VERSION 5.7 ;
BUSBITCHARS "[]" ;
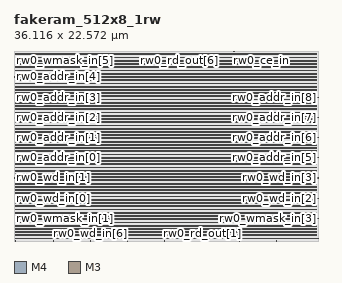
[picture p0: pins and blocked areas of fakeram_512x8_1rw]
MACRO fakeram_512x8_1rw
  FOREIGN fakeram_512x8_1rw 0 0 ;
  SYMMETRY X Y R90 ;
  SIZE 36.116 BY 22.572 ;
  CLASS BLOCK ;
  PIN rw0_wmask_in[0]
    DIRECTION INPUT ;
    USE SIGNAL ;
    SHAPE ABUTMENT ;
    PORT
      LAYER M4 ;
      RECT 0.000 0.276 0.072 0.300 ;
    END
  END rw0_wmask_in[0]
  PIN rw0_wmask_in[1]
    DIRECTION INPUT ;
    USE SIGNAL ;
    SHAPE ABUTMENT ;
    PORT
      LAYER M4 ;
      RECT 0.000 2.676 0.072 2.700 ;
    END
  END rw0_wmask_in[1]
  PIN rw0_wmask_in[2]
    DIRECTION INPUT ;
    USE SIGNAL ;
    SHAPE ABUTMENT ;
    PORT
      LAYER M4 ;
      RECT 36.044 0.276 36.116 0.300 ;
    END
  END rw0_wmask_in[2]
  PIN rw0_wmask_in[3]
    DIRECTION INPUT ;
    USE SIGNAL ;
    SHAPE ABUTMENT ;
    PORT
      LAYER M4 ;
      RECT 36.044 2.676 36.116 2.700 ;
    END
  END rw0_wmask_in[3]
  PIN rw0_wmask_in[4]
    DIRECTION INPUT ;
    USE SIGNAL ;
    SHAPE ABUTMENT ;
    PORT
      LAYER M3 ;
      RECT 0.207 22.518 0.225 22.572 ;
    END
  END rw0_wmask_in[4]
  PIN rw0_wmask_in[5]
    DIRECTION INPUT ;
    USE SIGNAL ;
    SHAPE ABUTMENT ;
    PORT
      LAYER M3 ;
      RECT 3.447 22.518 3.465 22.572 ;
    END
  END rw0_wmask_in[5]
  PIN rw0_wmask_in[6]
    DIRECTION INPUT ;
    USE SIGNAL ;
    SHAPE ABUTMENT ;
    PORT
      LAYER M3 ;
      RECT 6.687 22.518 6.705 22.572 ;
    END
  END rw0_wmask_in[6]
  PIN rw0_wmask_in[7]
    DIRECTION INPUT ;
    USE SIGNAL ;
    SHAPE ABUTMENT ;
    PORT
      LAYER M3 ;
      RECT 9.927 22.518 9.945 22.572 ;
    END
  END rw0_wmask_in[7]
  PIN rw0_wd_in[0]
    DIRECTION INPUT ;
    USE SIGNAL ;
    SHAPE ABUTMENT ;
    PORT
      LAYER M4 ;
      RECT 0.000 5.076 0.072 5.100 ;
    END
  END rw0_wd_in[0]
  PIN rw0_wd_in[1]
    DIRECTION INPUT ;
    USE SIGNAL ;
    SHAPE ABUTMENT ;
    PORT
      LAYER M4 ;
      RECT 0.000 7.476 0.072 7.500 ;
    END
  END rw0_wd_in[1]
  PIN rw0_wd_in[2]
    DIRECTION INPUT ;
    USE SIGNAL ;
    SHAPE ABUTMENT ;
    PORT
      LAYER M4 ;
      RECT 36.044 5.076 36.116 5.100 ;
    END
  END rw0_wd_in[2]
  PIN rw0_wd_in[3]
    DIRECTION INPUT ;
    USE SIGNAL ;
    SHAPE ABUTMENT ;
    PORT
      LAYER M4 ;
      RECT 36.044 7.476 36.116 7.500 ;
    END
  END rw0_wd_in[3]
  PIN rw0_wd_in[4]
    DIRECTION INPUT ;
    USE SIGNAL ;
    SHAPE ABUTMENT ;
    PORT
      LAYER M3 ;
      RECT 0.207 0.000 0.225 0.054 ;
    END
  END rw0_wd_in[4]
  PIN rw0_wd_in[5]
    DIRECTION INPUT ;
    USE SIGNAL ;
    SHAPE ABUTMENT ;
    PORT
      LAYER M3 ;
      RECT 4.635 0.000 4.653 0.054 ;
    END
  END rw0_wd_in[5]
  PIN rw0_wd_in[6]
    DIRECTION INPUT ;
    USE SIGNAL ;
    SHAPE ABUTMENT ;
    PORT
      LAYER M3 ;
      RECT 9.063 0.000 9.081 0.054 ;
    END
  END rw0_wd_in[6]
  PIN rw0_wd_in[7]
    DIRECTION INPUT ;
    USE SIGNAL ;
    SHAPE ABUTMENT ;
    PORT
      LAYER M3 ;
      RECT 13.491 0.000 13.509 0.054 ;
    END
  END rw0_wd_in[7]
  PIN rw0_rd_out[0]
    DIRECTION OUTPUT ;
    USE SIGNAL ;
    SHAPE ABUTMENT ;
    PORT
      LAYER M3 ;
      RECT 17.919 0.000 17.937 0.054 ;
    END
  END rw0_rd_out[0]
  PIN rw0_rd_out[1]
    DIRECTION OUTPUT ;
    USE SIGNAL ;
    SHAPE ABUTMENT ;
    PORT
      LAYER M3 ;
      RECT 22.347 0.000 22.365 0.054 ;
    END
  END rw0_rd_out[1]
  PIN rw0_rd_out[2]
    DIRECTION OUTPUT ;
    USE SIGNAL ;
    SHAPE ABUTMENT ;
    PORT
      LAYER M3 ;
      RECT 26.775 0.000 26.793 0.054 ;
    END
  END rw0_rd_out[2]
  PIN rw0_rd_out[3]
    DIRECTION OUTPUT ;
    USE SIGNAL ;
    SHAPE ABUTMENT ;
    PORT
      LAYER M3 ;
      RECT 31.203 0.000 31.221 0.054 ;
    END
  END rw0_rd_out[3]
  PIN rw0_rd_out[4]
    DIRECTION OUTPUT ;
    USE SIGNAL ;
    SHAPE ABUTMENT ;
    PORT
      LAYER M3 ;
      RECT 13.167 22.518 13.185 22.572 ;
    END
  END rw0_rd_out[4]
  PIN rw0_rd_out[5]
    DIRECTION OUTPUT ;
    USE SIGNAL ;
    SHAPE ABUTMENT ;
    PORT
      LAYER M3 ;
      RECT 16.407 22.518 16.425 22.572 ;
    END
  END rw0_rd_out[5]
  PIN rw0_rd_out[6]
    DIRECTION OUTPUT ;
    USE SIGNAL ;
    SHAPE ABUTMENT ;
    PORT
      LAYER M3 ;
      RECT 19.647 22.518 19.665 22.572 ;
    END
  END rw0_rd_out[6]
  PIN rw0_rd_out[7]
    DIRECTION OUTPUT ;
    USE SIGNAL ;
    SHAPE ABUTMENT ;
    PORT
      LAYER M3 ;
      RECT 22.887 22.518 22.905 22.572 ;
    END
  END rw0_rd_out[7]
  PIN rw0_addr_in[0]
    DIRECTION INPUT ;
    USE SIGNAL ;
    SHAPE ABUTMENT ;
    PORT
      LAYER M4 ;
      RECT 0.000 9.876 0.072 9.900 ;
    END
  END rw0_addr_in[0]
  PIN rw0_addr_in[1]
    DIRECTION INPUT ;
    USE SIGNAL ;
    SHAPE ABUTMENT ;
    PORT
      LAYER M4 ;
      RECT 0.000 12.276 0.072 12.300 ;
    END
  END rw0_addr_in[1]
  PIN rw0_addr_in[2]
    DIRECTION INPUT ;
    USE SIGNAL ;
    SHAPE ABUTMENT ;
    PORT
      LAYER M4 ;
      RECT 0.000 14.676 0.072 14.700 ;
    END
  END rw0_addr_in[2]
  PIN rw0_addr_in[3]
    DIRECTION INPUT ;
    USE SIGNAL ;
    SHAPE ABUTMENT ;
    PORT
      LAYER M4 ;
      RECT 0.000 17.076 0.072 17.100 ;
    END
  END rw0_addr_in[3]
  PIN rw0_addr_in[4]
    DIRECTION INPUT ;
    USE SIGNAL ;
    SHAPE ABUTMENT ;
    PORT
      LAYER M4 ;
      RECT 0.000 19.476 0.072 19.500 ;
    END
  END rw0_addr_in[4]
  PIN rw0_addr_in[5]
    DIRECTION INPUT ;
    USE SIGNAL ;
    SHAPE ABUTMENT ;
    PORT
      LAYER M4 ;
      RECT 36.044 9.876 36.116 9.900 ;
    END
  END rw0_addr_in[5]
  PIN rw0_addr_in[6]
    DIRECTION INPUT ;
    USE SIGNAL ;
    SHAPE ABUTMENT ;
    PORT
      LAYER M4 ;
      RECT 36.044 12.276 36.116 12.300 ;
    END
  END rw0_addr_in[6]
  PIN rw0_addr_in[7]
    DIRECTION INPUT ;
    USE SIGNAL ;
    SHAPE ABUTMENT ;
    PORT
      LAYER M4 ;
      RECT 36.044 14.676 36.116 14.700 ;
    END
  END rw0_addr_in[7]
  PIN rw0_addr_in[8]
    DIRECTION INPUT ;
    USE SIGNAL ;
    SHAPE ABUTMENT ;
    PORT
      LAYER M4 ;
      RECT 36.044 17.076 36.116 17.100 ;
    END
  END rw0_addr_in[8]
  PIN rw0_we_in
    DIRECTION INPUT ;
    USE SIGNAL ;
    SHAPE ABUTMENT ;
    PORT
      LAYER M3 ;
      RECT 26.127 22.518 26.145 22.572 ;
    END
  END rw0_we_in
  PIN rw0_ce_in
    DIRECTION INPUT ;
    USE SIGNAL ;
    SHAPE ABUTMENT ;
    PORT
      LAYER M3 ;
      RECT 29.367 22.518 29.385 22.572 ;
    END
  END rw0_ce_in
  PIN rw0_clk
    DIRECTION INPUT ;
    USE SIGNAL ;
    SHAPE ABUTMENT ;
    PORT
      LAYER M3 ;
      RECT 32.607 22.518 32.625 22.572 ;
    END
  END rw0_clk
  PIN VSS
    DIRECTION INOUT ;
    USE GROUND ;
    PORT
      LAYER M4 ;
      RECT 0.216 0.240 35.900 0.336 ;
      RECT 0.216 1.008 35.900 1.104 ;
      RECT 0.216 1.776 35.900 1.872 ;
      RECT 0.216 2.544 35.900 2.640 ;
      RECT 0.216 3.312 35.900 3.408 ;
      RECT 0.216 4.080 35.900 4.176 ;
      RECT 0.216 4.848 35.900 4.944 ;
      RECT 0.216 5.616 35.900 5.712 ;
      RECT 0.216 6.384 35.900 6.480 ;
      RECT 0.216 7.152 35.900 7.248 ;
      RECT 0.216 7.920 35.900 8.016 ;
      RECT 0.216 8.688 35.900 8.784 ;
      RECT 0.216 9.456 35.900 9.552 ;
      RECT 0.216 10.224 35.900 10.320 ;
      RECT 0.216 10.992 35.900 11.088 ;
      RECT 0.216 11.760 35.900 11.856 ;
      RECT 0.216 12.528 35.900 12.624 ;
      RECT 0.216 13.296 35.900 13.392 ;
      RECT 0.216 14.064 35.900 14.160 ;
      RECT 0.216 14.832 35.900 14.928 ;
      RECT 0.216 15.600 35.900 15.696 ;
      RECT 0.216 16.368 35.900 16.464 ;
      RECT 0.216 17.136 35.900 17.232 ;
      RECT 0.216 17.904 35.900 18.000 ;
      RECT 0.216 18.672 35.900 18.768 ;
      RECT 0.216 19.440 35.900 19.536 ;
      RECT 0.216 20.208 35.900 20.304 ;
      RECT 0.216 20.976 35.900 21.072 ;
      RECT 0.216 21.744 35.900 21.840 ;
    END
  END VSS
  PIN VDD
    DIRECTION INOUT ;
    USE POWER ;
    PORT
      LAYER M4 ;
      RECT 0.216 0.624 35.900 0.720 ;
      RECT 0.216 1.392 35.900 1.488 ;
      RECT 0.216 2.160 35.900 2.256 ;
      RECT 0.216 2.928 35.900 3.024 ;
      RECT 0.216 3.696 35.900 3.792 ;
      RECT 0.216 4.464 35.900 4.560 ;
      RECT 0.216 5.232 35.900 5.328 ;
      RECT 0.216 6.000 35.900 6.096 ;
      RECT 0.216 6.768 35.900 6.864 ;
      RECT 0.216 7.536 35.900 7.632 ;
      RECT 0.216 8.304 35.900 8.400 ;
      RECT 0.216 9.072 35.900 9.168 ;
      RECT 0.216 9.840 35.900 9.936 ;
      RECT 0.216 10.608 35.900 10.704 ;
      RECT 0.216 11.376 35.900 11.472 ;
      RECT 0.216 12.144 35.900 12.240 ;
      RECT 0.216 12.912 35.900 13.008 ;
      RECT 0.216 13.680 35.900 13.776 ;
      RECT 0.216 14.448 35.900 14.544 ;
      RECT 0.216 15.216 35.900 15.312 ;
      RECT 0.216 15.984 35.900 16.080 ;
      RECT 0.216 16.752 35.900 16.848 ;
      RECT 0.216 17.520 35.900 17.616 ;
      RECT 0.216 18.288 35.900 18.384 ;
      RECT 0.216 19.056 35.900 19.152 ;
      RECT 0.216 19.824 35.900 19.920 ;
      RECT 0.216 20.592 35.900 20.688 ;
      RECT 0.216 21.360 35.900 21.456 ;
      RECT 0.216 22.128 35.900 22.224 ;
    END
  END VDD
  OBS
    LAYER M1 ;
    RECT 0 0 36.116 22.572 ;
    LAYER M2 ;
    RECT 0 0 36.116 22.572 ;
    LAYER M3 ;
    RECT 0 0 36.116 22.572 ;
    LAYER M4 ;
    RECT 0 0 36.116 22.572 ;
  END
END fakeram_512x8_1rw

END LIBRARY
